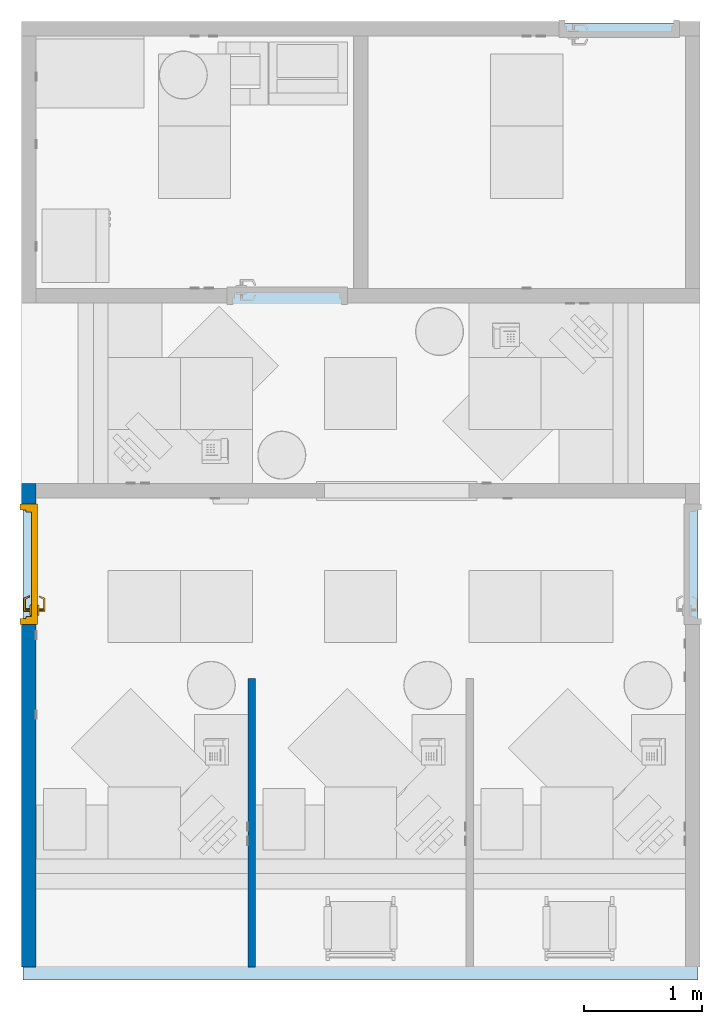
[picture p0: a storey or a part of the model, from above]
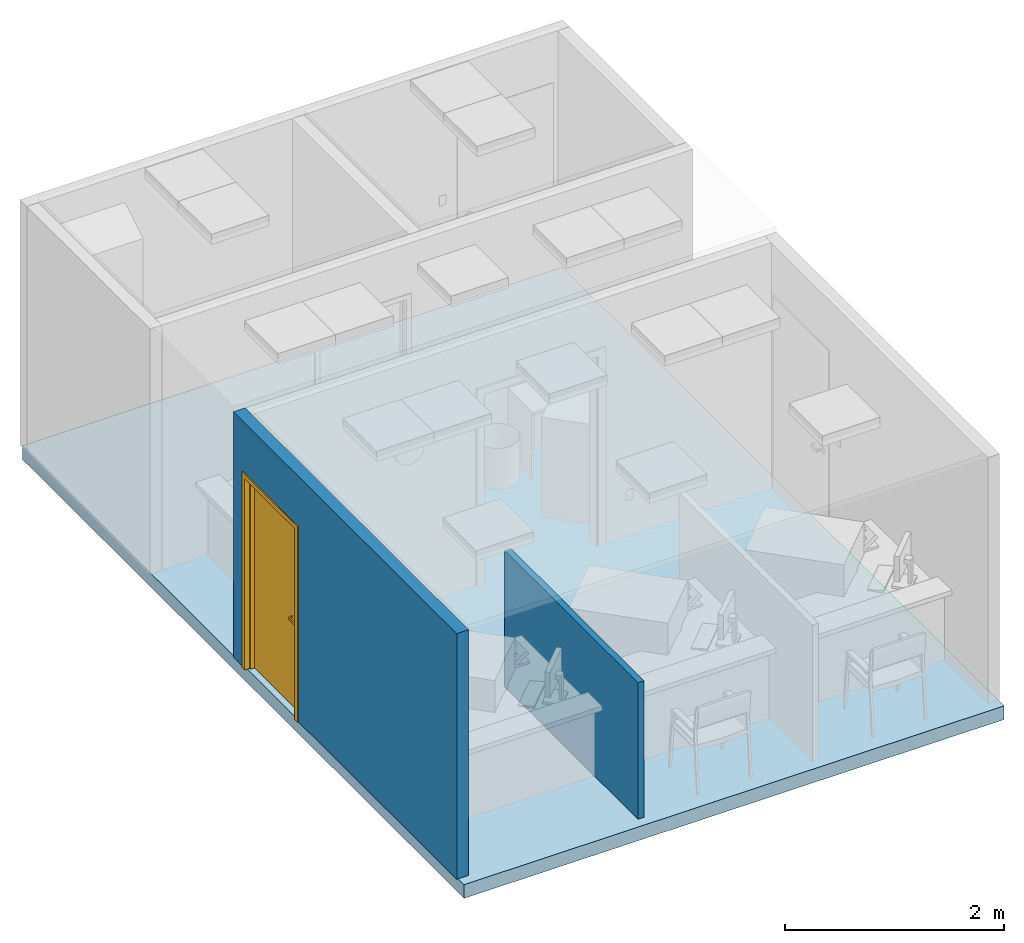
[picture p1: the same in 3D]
Properties of the parts of a building model (IFC2X3)

# File
Description: ViewDefinition [CoordinationView_V2.0]
File name: (ROOM CODE)
Time: 2018-06-28T02:08:09
Written by: The EXPRESS Data Manager Version 5.02.0100.07 : 28 Aug 2013
Made in: 20170223_1515(x64) - Exporter 18.0.0.420 - Alternate UI 18.0.0.420
Comment: STEP Physical File produced by: The EXPRESS Data Manager Version 5.02.0100.07 : 28 Aug 2013 * Module: EDMstepFileFactory/EDMstandAlone * Creation date: Thu Jun 28 02:08:09 2018 * Host: L106-OKC * Database: C:\Users\BHR~1.SPU\AppData\Local\Temp\{9B6AAEC2-433F-4AC2-803A-3ABD21A36A43}\ifc * Database version: 5507 * Database creation date: Thu Jun 28 02:08:07 2018 * Schema: IFC2X3 * Model: DataRepository.ifc * Model creation date: Thu Jun 28 02:08:07 2018 * Header model: DataRepository.ifc_HeaderModel * Header model creation date: Thu Jun 28 02:08:07 2018 * EDMuser: sdai-user * EDMgroup: sdai-group * License ID and type: 5605 : Permanent license. Expiry date: * EDMstepFileFactory options: 020000

# IfcProject, (ROOM CODE)
LongName: ROOM NAME (ROOM CODE); Phase: DRAFT

# IfcSite, Default
RefLatitude: 42, 21, 31, 181945; RefLongitude: -71, -3, -24, -263305; RefElevation: 0 ft

# IfcBuilding, OUTPATIENT / PACT CLINIC (Ch. 265)
LongName: OUTPATIENT / PACT CLINIC (Ch. 265)
Pset_BuildingCommon - NumberOfStoreys: 1

# IfcBuildingStorey, DATUM
In: OUTPATIENT / PACT CLINIC (Ch. 265)
LongName: DATUM; Elevation: 0 ft

# IfcSpace (4)
In: DATUM
InteriorOrExteriorSpace: INTERNAL
Pset_SpaceCommon - Category: Rooms
Name | LongName | Reference
 | COPY | COPY
 | STORAGE | STORAGE
 | WORKSPACE | WORKSPACE
RCP03 | RECEPTION | RECEPTION RCP03

# IfcBuildingElementProxy: 24" x 24" (4)
Type - Classification: D3040100 Air Distribution Systems (Uniformat)
Pset_BuildingElementProxyCommon - Reference: 24" x 24"
Name (Supply Diffuser:24" x 24":...) | In
1456524
1456709 | RCP03
1456749
1456785

# IfcBuildingElementProxy: 24" x 24" (2)
Type - Classification: D3040200 Exhaust Ventilation Systems (Uniformat)
Pset_BuildingElementProxyCommon - Reference: 24" x 24"
Name (Return Register:24" x 24":...) | In
1456525
1456710 | RCP03

# IfcBuildingElementProxy: 48" x 84", Passage Opening-Cased:48" x 84":1715645
Type - Material: Door - Frame
Pset_BuildingElementProxyCommon - Reference: 48" x 84"

# IfcBuildingElementProxy: A1015 Telephone_Desk Multi-Line (5)
Type - Classification: VV (Uniformat)
Pset_BuildingElementProxyCommon - Reference: A1015 Telephone_Desk Multi-Line
Name (A1015 - Telephone, Desk, Multiple Line:A1015 Telephone_Desk Multi-Line:...) | In
801328 | RCP03
1443435 | RCP03
1443459 | RCP03
1651907
1652184

# IfcBuildingElementProxy: C04F0 - Cabinet, U-C-B, 1 Shelf, 2 Half DR, 2 DO, 36x36x22, C04F0 - Cabinet, U-C-B, 1 Shelf, 2 Half DR, 2 DO, 36x36x22:C04F0 - Cabinet, U-C-B, 1 Shelf, 2 Half DR, 2 DO, 36x36x22:1764358
Type - Classification: CC (Uniformat)
Pset_BuildingElementProxyCommon - Reference: C04F0 - Cabinet, U-C-B, 1 Shelf, 2 Half DR, 2 DO, 36x36x22

# IfcBuildingElementProxy: CD040 - Cabinet, W-H, 2 Shelf, 2 DO, Sloping Top, 38x36x13, CD040 - Cabinet, W-H, 2 Shelf, 2 DO, Sloping Top, 38x36x13:CD040 - Cabinet, W-H, 2 Shelf, 2 DO, Sloping Top, 38x36x13:1764357
Type - Classification: CC (Uniformat)
Pset_BuildingElementProxyCommon - Reference: CD040 - Cabinet, W-H, 2 Shelf, 2 DO, Sloping Top, 38x36x13

# IfcBuildingElementProxy: CT020 - Countertop, Solid Surface - No Opening, CT020 - Countertop, Solid Surface - No Opening:CT020 - Countertop, Solid Surface - No Opening:1445980
Type - Classification: CC (Uniformat)
Pset_BuildingElementProxyCommon - Reference: CT020 - Countertop, Solid Surface - No Opening

# IfcBuildingElementProxy: Duplex (15)
Pset_BuildingElementProxyCommon - Reference: Duplex
Name (Outlet, Duplex, Wall:Duplex:...) | In
1568000
1568022
1568058
1568088
1568129
1568203
1568375 | RCP03
1568399 | RCP03
1568430 | RCP03
1568469 | RCP03
1770751 | RCP03
1770815 | RCP03
1770899 | RCP03
1895509
1895511

# IfcBuildingElementProxy: E0130 - Workstation, Documentation, Operating, L-Shaped (2)
Type - Classification: CC (Uniformat)
Pset_BuildingElementProxyCommon - Reference: E0130 - Workstation, Documentation, Operating, L-Shaped
Name (E0130 - Workstation, Documentation, Operating, L-Shaped:E0130 - Workstation, Documentation, Operating, L-Shaped:...)
1651910
1652187

# IfcBuildingElementProxy: E0130 - Workstation, Documentation, Operating, L-Shaped, 5-10, E0130 - Workstation, Documentation, Operating, L-Shaped, 5-10:E0130 - Workstation, Documentation, Operating, L-Shaped, 5-10:1443439
In: RCP03
Type - Classification: CC (Uniformat)
Pset_BuildingElementProxyCommon - Reference: E0130 - Workstation, Documentation, Operating, L-Shaped, 5-10

# IfcBuildingElementProxy: E0130 - Workstation, Documentation, Operating, L-Shaped, 5-10.5 (2)
In: RCP03
Type - Classification: CC (Uniformat)
Pset_BuildingElementProxyCommon - Reference: E0130 - Workstation, Documentation, Operating, L-Shaped, 5-10.5
Name (E0130 - Workstation, Documentation, Operating, L-Shaped, 5-10.5:E0130 - Workstation, Documentation, Operating, L-Shaped, 5-10.5:...)
1441602
1443463

# IfcBuildingElementProxy: F0205 - Chair, Side With Arms (2)
In: RCP03
Type - Classification: VV (Uniformat)
Pset_BuildingElementProxyCommon - Reference: F0205 - Chair, Side With Arms
Name (F0205 - Chair, Side With Arms:F0205 - Chair, Side With Arms:...)
1896422
1896790

# IfcBuildingElementProxy: F0275 - Chair, Swivel, High Back (2) (5)
Type - Classification: VV (Uniformat)
Pset_BuildingElementProxyCommon - Reference: F0275 - Chair, Swivel, High Back (2)
Name (F0275 - Chair, Swivel, High Back (2):F0275 - Chair, Swivel, High Back (2):...) | In
801330 | RCP03
1443436 | RCP03
1443460 | RCP03
1651908
1652185

# IfcBuildingElementProxy: F0404 - Pedestal File Mobile (3)
In: RCP03
Type - Classification: VV (Uniformat)
Pset_BuildingElementProxyCommon - Reference: F0404 - Pedestal File Mobile
Name (F0404 - Pedestal File Mobile:F0404 - Pedestal File Mobile:...)
1934306
1934307
1934308

# IfcBuildingElementProxy: F2000 - Basket, Wastepaper (6)
Type - Classification: VV (Uniformat)
Pset_BuildingElementProxyCommon - Reference: F2000 - Basket, Wastepaper
Name (F2000 - Basket, Wastepaper:F2000 - Basket, Wastepaper:...) | In
801331 | RCP03
1443437 | RCP03
1443461 | RCP03
1651909
1652186
1767244

# IfcBuildingElementProxy: F2550 - Shredder, Paper Heavy Duty, F2550 - Shredder, Paper Heavy Duty:F2550 - Shredder, Paper Heavy Duty:1450435
Type - Classification: VV (Uniformat)
Pset_BuildingElementProxyCommon - Reference: F2550 - Shredder, Paper Heavy Duty

# IfcBuildingElementProxy: F3200 - Clock, Battery, 12in Dia, F3200 - Clock, Battery, 12in Dia:F3200 - Clock, Battery, 12in Dia:801332
In: RCP03
Type - Classification: VV (Uniformat)
Pset_BuildingElementProxyCommon - Reference: F3200 - Clock, Battery, 12in Dia

# IfcBuildingElementProxy: M1801 - Computer with Flat Panel Monitor (5)
Type - Classification: VV (Uniformat)
Pset_BuildingElementProxyCommon - Reference: M1801 - Computer with Flat Panel Monitor
Name (M1801 - Computer with Flat Panel Monitor:M1801 - Computer with Flat Panel Monitor:...) | In
1447346 | RCP03
1553055 | RCP03
1553056 | RCP03
1651922
1652188

# IfcBuildingElementProxy: M1810 - Copier, Floor Standing, Digital 42"x 27", M1810 - Copier Floor Standing Digital:M1810 - Copier, Floor Standing, Digital 42"x 27":1769388
Type - Classification: VV (Uniformat); Material: Plastic - Gray,Dark, Plastic - White
Pset_BuildingElementProxyCommon - Reference: M1810 - Copier, Floor Standing, Digital 42"x 27"

# IfcBuildingElementProxy: Single (5)
Pset_BuildingElementProxyCommon - Reference: Single
Name (Switch, Single:Single:...) | In
1568884 | RCP03
1568907 | RCP03
1568935
1568955
1568980

# IfcBuildingElementProxy: Telephone/Data (7)
Pset_BuildingElementProxyCommon - Reference: Telephone/Data
Name (Outlet, Communications:Telephone/Data:...) | In
1568718
1770752 | RCP03
1770816 | RCP03
1770900 | RCP03
1895510
1895512
1896863

# IfcCovering: Compound Ceiling:2' x 2' ACT System (4)
In: DATUM
PredefinedType: CEILING; Classification: C3030210 Suspended Ceilings - Acoustical (Uniformat); Material: <Unnamed> 0.135417 ft, Acoustic Ceiling Tile 24 x 24 0.0520833 ft
Pset_CoveringCommon - Reference: 2' x 2' ACT System; Finish: Acoustic Ceiling Tile 24 x 24;; TotalThickness: 0.1875 ft
Name (Compound Ceiling:2' x 2' ACT System:...)
801306
1455046
1455100
1455580

# IfcDoor: 36" x 84" (4)
In: DATUM
Type - ParameterTakesPrecedence: no; Sizeable: no; Classification: C1020 Interior Doors (Uniformat)
OverallHeight: 7.16667 ft; OverallWidth: 3.33333 ft
Pset_DoorCommon - IsExternal: no; Reference: 36" x 84"
Name (Single - Flush:36" x 84":...)
1508736
1508737
1508741
1551022

# IfcFlowTerminal: 2'x2' (11)
Type - Classification: D5020210 Lighting - Fluorescent (Uniformat)
Pset_DistributionFlowElementCommon - Reference: 2'x2'
Name (Troffer Light:2'x2':...) | In
1021224 | RCP03
1455600
1455763
1455923 | RCP03
1455958 | RCP03
1456089 | RCP03
1456090 | RCP03
1456091 | RCP03
1456458
1767604
1767651

# IfcFurnishingElement: Transaction Counter (2)
In: RCP03
Type - ElementType: Transaction Counter
Name
Transaction Counter:Transaction Counter:1895816
Transaction Counter1:Transaction Counter:1978271

# IfcOpeningElement: Opening (7)
In: DATUM
Name
Single - Flush:36" x 84":1551022:1
Basic Wall:Interior - 4 7/8":1442844 | Classification: B2010 Exterior Walls (Uniformat)
Single - Flush:36" x 84":1508741:1
Single - Flush:36" x 84":1508736:1
Single - Flush:36" x 84":1508737:1
Basic Wall:Interior - 4 7/8":1897111:1 | Classification: B2010 Exterior Walls (Uniformat)
Basic Wall:Interior - 4 7/8":1897111:2 | Classification: B2010 Exterior Walls (Uniformat)

# IfcSlab: Floor:Generic - 6", Floor:Generic - 6":801320
In: DATUM
PredefinedType: FLOOR; Classification: B1010 Floor Construction (Uniformat); Material: <Unnamed> 0.5 ft
Pset_SlabCommon - Reference: Generic - 6"; IsExternal: no; LoadBearing: no; PitchAngle: 0 deg

# IfcWallStandardCase: Basic Wall:Interior - 4 7/8" (11)
In: DATUM
Type - PredefinedType: STANDARD; Material: <Unnamed> 0.40625 ft
Classification: B2010 Exterior Walls (Uniformat)
Pset_WallCommon - LoadBearing: no; Reference: Interior - 4 7/8"; ExtendToStructure: no; IsExternal: yes
Name (Basic Wall:Interior - 4 7/8":...)
801337
1442799
1442844
1444095
1445727
1445909
1553023
1553043
1766787
1766885
1897111

# IfcWallStandardCase: Basic Wall:Systems Wall (2)
In: DATUM
Type - PredefinedType: STANDARD; Material: <Unnamed> 0.208333 ft
Classification: B2010 Exterior Walls (Uniformat)
Pset_WallCommon - LoadBearing: no; ExtendToStructure: no; IsExternal: yes; Reference: Systems Wall
Name (Basic Wall:Systems Wall:...)
1443116
1443458
